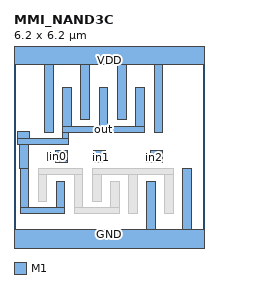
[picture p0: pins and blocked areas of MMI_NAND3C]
MACRO MMI_NAND3C
	CLASS CORE ;
	FOREIGN MMI_NAND3C 0 0 ;
	SIZE 6.2 BY 6.2 ;
	SYMMETRY X Y ;
	SITE CORE1 ;
	PIN out
		DIRECTION output ;
		USE SIGNAL ;
		PORT
			LAYER M1 ;
			RECT 1.595 3.775 1.875 5.05 ;
			LAYER M1 ;
			RECT 2.775 3.775 3.055 5.05 ;
			LAYER M1 ;
			RECT 3.98 3.775 4.26 5.05 ;
			LAYER M1 ;
			RECT 0.12 3.375 0.5 3.6 ;
			LAYER M1 ;
			RECT 1.595 3.58 4.26 3.775 ;
			LAYER M1 ;
			RECT 1.595 3.375 1.79 3.58 ;
			LAYER M1 ;
			RECT 0.12 3.18 1.79 3.375 ;
			LAYER M1 ;
			RECT 0.19 2.395 0.475 3.18 ;
			LAYER M1 ;
			RECT 0.2 1.12 0.48 2.395 ;
			LAYER M1 ;
			RECT 1.38 1.12 1.66 1.985 ;
			LAYER M1 ;
			RECT 0.2 0.925 1.66 1.12 ;
		END
		AntennaDiffArea 3.3341 ;
	END out
	PIN in1
		DIRECTION input ;
		USE SIGNAL ;
		PORT
			LAYER M1 ;
			RECT 2.6 2.885 2.98 2.98 ;
			LAYER M1 ;
			RECT 2.6 2.605 3.065 2.885 ;
			LAYER M1 ;
			RECT 2.6 2.6 2.98 2.605 ;
		END
		AntennaGateArea 1.155 ;
	END in1
	PIN GND
		DIRECTION inout ;
		USE GROUND ;
		PORT
			LAYER M1 ;
			RECT 4.33 0.42 4.61 1.985 ;
			LAYER M1 ;
			RECT 5.51 0.42 5.79 2.395 ;
			LAYER M1 ;
			RECT 0 -0.42 6.2 0.42 ;
		END
	END GND
	PIN in2
		DIRECTION input ;
		USE SIGNAL ;
		PORT
			LAYER M1 ;
			RECT 4.46 2.885 4.84 2.98 ;
			LAYER M1 ;
			RECT 4.285 2.605 4.84 2.885 ;
			LAYER M1 ;
			RECT 4.46 2.6 4.84 2.605 ;
		END
		AntennaGateArea 1.155 ;
	END in2
	PIN VDD
		DIRECTION inout ;
		USE POWER ;
		PORT
			LAYER M1 ;
			RECT 0 5.78 6.2 6.62 ;
			LAYER M1 ;
			RECT 1.005 3.58 1.285 5.78 ;
			LAYER M1 ;
			RECT 2.185 3.99 2.465 5.78 ;
			LAYER M1 ;
			RECT 3.39 3.99 3.67 5.78 ;
			LAYER M1 ;
			RECT 4.57 3.58 4.85 5.78 ;
		END
	END VDD
	PIN in0
		DIRECTION input ;
		USE SIGNAL ;
		PORT
			LAYER M1 ;
			RECT 1.36 2.93 1.74 2.98 ;
			LAYER M1 ;
			RECT 1.1 2.65 1.74 2.93 ;
			LAYER M1 ;
			RECT 1.36 2.6 1.74 2.65 ;
		END
		AntennaGateArea 1.155 ;
	END in0
	OBS
		LAYER M1 ;
		RECT 0.79 2.395 2.245 2.4 ;
		LAYER M1 ;
		RECT 0.79 2.21 2.25 2.395 ;
		LAYER M1 ;
		RECT 2.555 2.21 5.2 2.4 ;
		LAYER M1 ;
		RECT 0.79 1.335 1.07 2.21 ;
		LAYER M1 ;
		RECT 1.97 1.12 2.25 2.21 ;
		LAYER M1 ;
		RECT 2.56 1.335 2.84 2.21 ;
		LAYER M1 ;
		RECT 3.15 1.12 3.43 1.985 ;
		LAYER M1 ;
		RECT 1.97 0.925 3.43 1.12 ;
		LAYER M1 ;
		RECT 3.74 0.925 4.02 2.21 ;
		LAYER M1 ;
		RECT 4.92 0.925 5.2 2.21 ;
	END
END MMI_NAND3C
